VERSION 5.7 ;
  NOWIREEXTENSIONATPIN ON ;
  DIVIDERCHAR "/" ;
  BUSBITCHARS "[]" ;
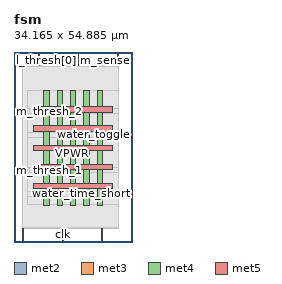
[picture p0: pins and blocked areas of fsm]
MACRO fsm
  CLASS BLOCK ;
  FOREIGN fsm ;
  ORIGIN 0.000 0.000 ;
  SIZE 34.165 BY 54.885 ;
  PIN clk
    DIRECTION INPUT ;
    USE SIGNAL ;
    PORT
      LAYER met2 ;
        RECT 13.890 0.000 14.170 4.000 ;
    END
  END clk
  PIN l_sense
    DIRECTION INPUT ;
    USE SIGNAL ;
    PORT
      LAYER met2 ;
        RECT 18.490 50.885 18.770 54.885 ;
    END
  END l_sense
  PIN l_thresh[0]
    DIRECTION INPUT ;
    USE SIGNAL ;
    PORT
      LAYER met2 ;
        RECT 6.990 50.885 7.270 54.885 ;
    END
  END l_thresh[0]
  PIN l_thresh[1]
    DIRECTION INPUT ;
    USE SIGNAL ;
    PORT
      LAYER met2 ;
        RECT 2.390 0.000 2.670 4.000 ;
    END
  END l_thresh[1]
  PIN m_sense
    DIRECTION INPUT ;
    USE SIGNAL ;
    PORT
      LAYER met2 ;
        RECT 29.990 50.885 30.270 54.885 ;
    END
  END m_sense
  PIN m_thresh_1
    DIRECTION INPUT ;
    USE SIGNAL ;
    PORT
      LAYER met3 ;
        RECT 0.000 20.440 4.000 21.040 ;
    END
  END m_thresh_1
  PIN m_thresh_2
    DIRECTION INPUT ;
    USE SIGNAL ;
    PORT
      LAYER met3 ;
        RECT 0.000 37.440 4.000 38.040 ;
    END
  END m_thresh_2
  PIN water_time_long
    DIRECTION INPUT ;
    USE SIGNAL ;
    PORT
      LAYER met2 ;
        RECT 25.390 0.000 25.670 4.000 ;
    END
  END water_time_long
  PIN water_time_short
    DIRECTION INPUT ;
    USE SIGNAL ;
    PORT
      LAYER met3 ;
        RECT 30.165 13.640 34.165 14.240 ;
    END
  END water_time_short
  PIN water_toggle
    DIRECTION OUTPUT TRISTATE ;
    USE SIGNAL ;
    PORT
      LAYER met3 ;
        RECT 30.165 30.640 34.165 31.240 ;
    END
  END water_toggle
  PIN VPWR
    DIRECTION INOUT ;
    USE POWER ;
    PORT
      LAYER met4 ;
        RECT 23.990 10.640 25.590 43.760 ;
    END
  END VPWR
  PIN VPWR
    DIRECTION INOUT ;
    USE POWER ;
    PORT
      LAYER met4 ;
        RECT 16.280 10.640 17.880 43.760 ;
    END
  END VPWR
  PIN VPWR
    DIRECTION INOUT ;
    USE POWER ;
    PORT
      LAYER met4 ;
        RECT 8.575 10.640 10.175 43.760 ;
    END
  END VPWR
  PIN VPWR
    DIRECTION INOUT ;
    USE POWER ;
    PORT
      LAYER met5 ;
        RECT 5.520 37.445 28.520 39.045 ;
    END
  END VPWR
  PIN VPWR
    DIRECTION INOUT ;
    USE POWER ;
    PORT
      LAYER met5 ;
        RECT 5.520 26.405 28.520 28.005 ;
    END
  END VPWR
  PIN VPWR
    DIRECTION INOUT ;
    USE POWER ;
    PORT
      LAYER met5 ;
        RECT 5.520 15.360 28.520 16.960 ;
    END
  END VPWR
  PIN VGND
    DIRECTION INOUT ;
    USE GROUND ;
    PORT
      LAYER met4 ;
        RECT 20.135 10.640 21.735 43.760 ;
    END
  END VGND
  PIN VGND
    DIRECTION INOUT ;
    USE GROUND ;
    PORT
      LAYER met4 ;
        RECT 12.430 10.640 14.030 43.760 ;
    END
  END VGND
  PIN VGND
    DIRECTION INOUT ;
    USE GROUND ;
    PORT
      LAYER met5 ;
        RECT 5.520 31.925 28.520 33.525 ;
    END
  END VGND
  PIN VGND
    DIRECTION INOUT ;
    USE GROUND ;
    PORT
      LAYER met5 ;
        RECT 5.520 20.880 28.520 22.480 ;
    END
  END VGND
  OBS
      LAYER li1 ;
        RECT 5.520 10.795 28.520 43.605 ;
      LAYER met1 ;
        RECT 2.370 10.640 30.290 43.760 ;
      LAYER met2 ;
        RECT 2.400 50.605 6.710 50.885 ;
        RECT 7.550 50.605 18.210 50.885 ;
        RECT 19.050 50.605 29.710 50.885 ;
        RECT 2.400 4.280 30.260 50.605 ;
        RECT 2.950 4.000 13.610 4.280 ;
        RECT 14.450 4.000 25.110 4.280 ;
        RECT 25.950 4.000 30.260 4.280 ;
      LAYER met3 ;
        RECT 4.000 38.440 30.165 43.685 ;
        RECT 4.400 37.040 30.165 38.440 ;
        RECT 4.000 31.640 30.165 37.040 ;
        RECT 4.000 30.240 29.765 31.640 ;
        RECT 4.000 21.440 30.165 30.240 ;
        RECT 4.400 20.040 30.165 21.440 ;
        RECT 4.000 14.640 30.165 20.040 ;
        RECT 4.000 13.240 29.765 14.640 ;
        RECT 4.000 10.715 30.165 13.240 ;
  END
END fsm
END LIBRARY

